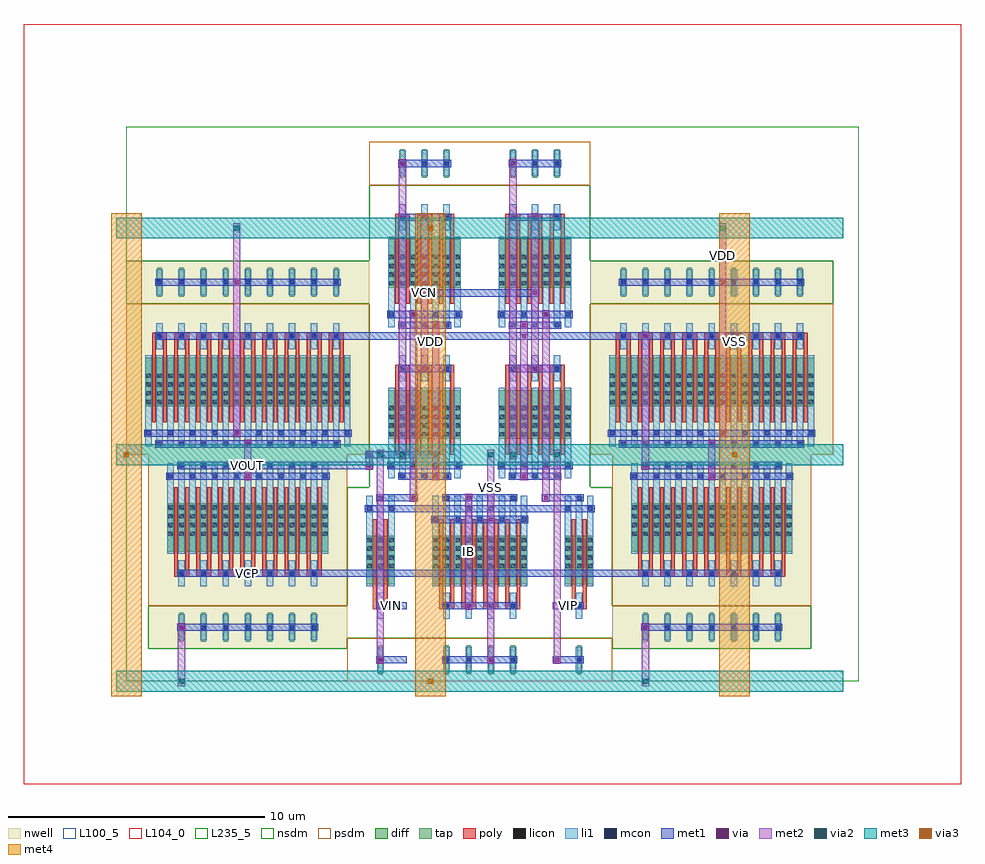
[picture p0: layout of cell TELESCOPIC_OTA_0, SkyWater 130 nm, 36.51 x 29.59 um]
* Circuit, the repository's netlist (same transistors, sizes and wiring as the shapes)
* NGSPICE file created from TELESCOPIC_OTA_0.ext - technology: sky130A

.subckt PMOS_S_43132956_X9_Y1_1774869329 a_200_252# a_230_378# w_0_0#
X0 a_230_378# a_200_252# w_0_0# w_0_0# sky130_fd_pr__pfet_01v8 ad=0.2646 pd=2.17 as=0.2646 ps=2.17 w=1.89 l=0.15 M=18
.ends

.subckt NMOS_4T_91638993_X3_Y2_1774869327 a_200_252# a_230_378# a_147_378# a_241_2408#
X0 a_230_378# a_200_252# a_147_378# a_241_2408# sky130_fd_pr__nfet_01v8 ad=0.2646 pd=2.17 as=0.2646 ps=2.17 w=1.89 l=0.15 M=12
.ends

.subckt PMOS_4T_19330511_X7_Y1_1774869328 a_200_252# a_230_378# w_0_0# a_147_378#
X0 a_230_378# a_200_252# a_147_378# w_0_0# sky130_fd_pr__pfet_01v8 ad=0.2646 pd=2.17 as=0.2646 ps=2.17 w=1.89 l=0.15 M=14
.ends

.subckt SCM_NMOS_27386274_X2_Y1_1774869330 a_200_252# a_402_378# a_147_378#
X0 a_402_378# a_200_252# a_147_378# a_147_378# sky130_fd_pr__nfet_01v8 ad=0.2646 pd=2.17 as=0.2646 ps=2.17 w=1.89 l=0.15 M=4
X1 a_200_252# a_200_252# a_147_378# a_147_378# sky130_fd_pr__nfet_01v8 ad=0.2646 pd=2.17 as=0.2646 ps=2.17 w=1.89 l=0.15 M=4
.ends

.subckt NMOS_4T_36089430_X1_Y1_1774869326 a_200_252# a_230_378# a_147_378# a_241_1232#
X0 a_230_378# a_200_252# a_147_378# a_241_1232# sky130_fd_pr__nfet_01v8 ad=0.2646 pd=2.17 as=0.50085 ps=4.31 w=1.89 l=0.15 M=2
.ends

.subckt TELESCOPIC_OTA_0 IB VCN VOUT VIP VIN VCP VSS VDD
XPMOS_S_43132956_X9_Y1_1774869329_0 m1_4010_1652# m1_914_1568# VDD PMOS_S_43132956_X9_Y1_1774869329
XNMOS_4T_91638993_X3_Y2_1774869327_0 VCN VOUT m1_2150_1400# VSS NMOS_4T_91638993_X3_Y2_1774869327
XPMOS_S_43132956_X9_Y1_1774869329_1 m1_4010_1652# m1_4526_1568# VDD PMOS_S_43132956_X9_Y1_1774869329
XNMOS_4T_91638993_X3_Y2_1774869327_1 VCN m1_4010_1652# m1_3236_1400# VSS NMOS_4T_91638993_X3_Y2_1774869327
XPMOS_4T_19330511_X7_Y1_1774869328_0 VCP VOUT VDD m1_914_1568# PMOS_4T_19330511_X7_Y1_1774869328
XPMOS_4T_19330511_X7_Y1_1774869328_1 VCP m1_4010_1652# VDD m1_4526_1568# PMOS_4T_19330511_X7_Y1_1774869328
XSCM_NMOS_27386274_X2_Y1_1774869330_0 IB m1_2838_1316# VSS SCM_NMOS_27386274_X2_Y1_1774869330
XNMOS_4T_36089430_X1_Y1_1774869326_0 VIN m1_2150_1400# m1_2838_1316# VSS NMOS_4T_36089430_X1_Y1_1774869326
XNMOS_4T_36089430_X1_Y1_1774869326_1 VIP m1_3236_1400# m1_2838_1316# VSS NMOS_4T_36089430_X1_Y1_1774869326
.ends

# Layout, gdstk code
from math import pi, radians
import gdstk
lib = gdstk.Library(unit=1e-6, precision=1e-09)
def R(c, l, rs):  # rectangles x0, y0, x1, y1
    for r in rs: c.add(gdstk.rectangle(r[:2], r[2:], *l))
def A(c, l, x, y, w, h, nx, ny, dx, dy):  # array of equal rectangles
    R(c, l, [(x+i*dx, y+j*dy, x+i*dx+w, y+j*dy+h) for i in range(nx) for j in range(ny)])
def P(c, l, *ps):  # polygons
    for p in ps: c.add(gdstk.Polygon(p, *l))
nwell = (64, 20)
diff = (65, 20)
tap = (65, 44)
poly = (66, 20)
licon = (66, 44)
li1 = (67, 20)
mcon = (67, 44)
met1 = (68, 20)
via = (68, 44)
met2 = (69, 20)
via2 = (69, 44)
met3 = (70, 20)
via3 = (70, 44)
met4 = (71, 20)
nsdm = (93, 44)
psdm = (94, 20)
L100_5 = (100, 5)
L104_0 = (104, 0)
L235_5 = (235, 5)

scm_nmos_27386274_x2_y1_ = lib.new_cell('SCM_NMOS_27386274_X2_Y1_1774869330')
R(scm_nmos_27386274_x2_y1_, diff, [(0.735,1.89,4.425,3.78)])
A(scm_nmos_27386274_x2_y1_, tap, 1.205, 6.16, 0.17, 1.12, 4, 1, 0.86, 0)
A(scm_nmos_27386274_x2_y1_, poly, 1, 1.26, 0.15, 3.36, 8, 1, 0.43, 0)
A(scm_nmos_27386274_x2_y1_, poly, 1, 4.485, 0.58, 0.27, 4, 1, 0.86, 0)
A(scm_nmos_27386274_x2_y1_, licon, 0.775, 1.97, 0.17, 0.17, 3, 4, 0.43, 0.34)
A(scm_nmos_27386274_x2_y1_, licon, 1.635, 1.97, 0.17, 0.17, 3, 4, 0.43, 0.34)
A(scm_nmos_27386274_x2_y1_, licon, 2.495, 1.97, 0.17, 0.17, 3, 4, 0.43, 0.34)
A(scm_nmos_27386274_x2_y1_, licon, 3.355, 1.97, 0.17, 0.17, 3, 4, 0.43, 0.34)
A(scm_nmos_27386274_x2_y1_, licon, 1.205, 4.535, 0.17, 0.17, 4, 2, 0.86, 2.1)
A(scm_nmos_27386274_x2_y1_, li1, 0.735, 0.335, 0.25, 3.53, 9, 1, 0.43, 0)
A(scm_nmos_27386274_x2_y1_, li1, 1.165, 4.115, 0.25, 1.01, 4, 2, 0.86, 2.1)
A(scm_nmos_27386274_x2_y1_, mcon, 0.775, 1.175, 0.17, 0.17, 5, 1, 0.86, 0)
A(scm_nmos_27386274_x2_y1_, mcon, 1.205, 4.535, 0.17, 0.17, 4, 2, 0.86, 2.1)
R(scm_nmos_27386274_x2_y1_, mcon, [(1.205,0.335,1.375,0.505), (3.785,0.335,3.955,0.505), (2.065,0.755,2.235,0.925), (2.925,0.755,3.095,0.925)])
R(scm_nmos_27386274_x2_y1_, met1, [(1.12,0.28,4.04,0.56), (1.98,0.7,3.18,0.98), (0.69,1.12,4.47,1.4), (1.12,4.48,4.04,4.76), (1.12,6.58,4.04,6.86)])
R(scm_nmos_27386274_x2_y1_, via, [(2.075,0.345,2.225,0.495), (2.935,1.185,3.085,1.335), (2.075,4.545,2.225,4.695), (2.935,6.645,3.085,6.795)])
R(scm_nmos_27386274_x2_y1_, met2, [(2.01,0.26,2.29,4.78), (2.87,1.1,3.15,6.88)])
R(scm_nmos_27386274_x2_y1_, nsdm, [(0,0,5.16,5.88)])
R(scm_nmos_27386274_x2_y1_, psdm, [(0,5.88,5.16,7.56)])
R(scm_nmos_27386274_x2_y1_, L100_5, [(0,0,5.16,7.56)])

pmos_s_43132956_x9_y1_17 = lib.new_cell('PMOS_S_43132956_X9_Y1_1774869329')
R(pmos_s_43132956_x9_y1_17, nwell, [(0,0,9.46,7.56)])
R(pmos_s_43132956_x9_y1_17, diff, [(0.735,1.89,8.725,3.78)])
A(pmos_s_43132956_x9_y1_17, tap, 1.205, 6.16, 0.17, 1.12, 9, 1, 0.86, 0)
A(pmos_s_43132956_x9_y1_17, poly, 1, 1.26, 0.15, 3.36, 18, 1, 0.43, 0)
A(pmos_s_43132956_x9_y1_17, poly, 1, 4.485, 0.58, 0.27, 9, 1, 0.86, 0)
A(pmos_s_43132956_x9_y1_17, licon, 0.775, 1.97, 0.17, 0.17, 3, 4, 0.43, 0.34)
A(pmos_s_43132956_x9_y1_17, licon, 1.635, 1.97, 0.17, 0.17, 3, 4, 0.43, 0.34)
A(pmos_s_43132956_x9_y1_17, licon, 2.495, 1.97, 0.17, 0.17, 3, 4, 0.43, 0.34)
A(pmos_s_43132956_x9_y1_17, licon, 3.355, 1.97, 0.17, 0.17, 3, 4, 0.43, 0.34)
A(pmos_s_43132956_x9_y1_17, licon, 4.215, 1.97, 0.17, 0.17, 3, 4, 0.43, 0.34)
A(pmos_s_43132956_x9_y1_17, licon, 5.075, 1.97, 0.17, 0.17, 3, 4, 0.43, 0.34)
A(pmos_s_43132956_x9_y1_17, licon, 5.935, 1.97, 0.17, 0.17, 3, 4, 0.43, 0.34)
A(pmos_s_43132956_x9_y1_17, licon, 6.795, 1.97, 0.17, 0.17, 3, 4, 0.43, 0.34)
A(pmos_s_43132956_x9_y1_17, licon, 7.655, 1.97, 0.17, 0.17, 3, 4, 0.43, 0.34)
A(pmos_s_43132956_x9_y1_17, licon, 1.205, 4.535, 0.17, 0.17, 9, 2, 0.86, 2.1)
A(pmos_s_43132956_x9_y1_17, li1, 0.735, 0.335, 0.25, 3.53, 19, 1, 0.43, 0)
A(pmos_s_43132956_x9_y1_17, li1, 1.165, 4.115, 0.25, 1.01, 9, 2, 0.86, 2.1)
A(pmos_s_43132956_x9_y1_17, mcon, 1.205, 0.335, 0.17, 0.17, 9, 2, 0.86, 4.2)
A(pmos_s_43132956_x9_y1_17, mcon, 0.775, 0.755, 0.17, 0.17, 10, 1, 0.86, 0)
A(pmos_s_43132956_x9_y1_17, mcon, 1.205, 6.635, 0.17, 0.17, 9, 1, 0.86, 0)
R(pmos_s_43132956_x9_y1_17, met1, [(1.12,0.28,8.34,0.56), (0.69,0.7,8.77,0.98), (1.12,4.48,8.34,4.76), (1.12,6.58,8.34,6.86)])
R(pmos_s_43132956_x9_y1_17, via, [(5.085,0.765,5.235,0.915), (5.085,6.645,5.235,6.795)])
R(pmos_s_43132956_x9_y1_17, met2, [(5.02,0.68,5.3,6.88)])
R(pmos_s_43132956_x9_y1_17, nsdm, [(0,5.88,9.46,7.56)])
R(pmos_s_43132956_x9_y1_17, psdm, [(0,0,9.46,5.88)])
R(pmos_s_43132956_x9_y1_17, L100_5, [(0,0,9.46,7.56)])

nmos_4t_91638993_x3_y2_1 = lib.new_cell('NMOS_4T_91638993_X3_Y2_1774869327')
R(nmos_4t_91638993_x3_y2_1, diff, [(0.735,1.89,3.565,3.78), (0.735,7.77,3.565,9.66)])
A(nmos_4t_91638993_x3_y2_1, tap, 1.205, 12.04, 0.17, 1.12, 3, 1, 0.86, 0)
A(nmos_4t_91638993_x3_y2_1, poly, 1, 1.26, 0.15, 3.36, 6, 2, 0.43, 5.88)
A(nmos_4t_91638993_x3_y2_1, poly, 1, 4.485, 0.58, 0.27, 3, 2, 0.86, 5.88)
A(nmos_4t_91638993_x3_y2_1, licon, 0.775, 1.97, 0.17, 0.17, 3, 4, 0.43, 0.34)
A(nmos_4t_91638993_x3_y2_1, licon, 1.635, 1.97, 0.17, 0.17, 3, 4, 0.43, 0.34)
A(nmos_4t_91638993_x3_y2_1, licon, 2.495, 1.97, 0.17, 0.17, 3, 4, 0.43, 0.34)
A(nmos_4t_91638993_x3_y2_1, licon, 1.205, 4.535, 0.17, 0.17, 3, 2, 0.86, 5.88)
A(nmos_4t_91638993_x3_y2_1, licon, 0.775, 7.85, 0.17, 0.17, 3, 4, 0.43, 0.34)
A(nmos_4t_91638993_x3_y2_1, licon, 1.635, 7.85, 0.17, 0.17, 3, 4, 0.43, 0.34)
A(nmos_4t_91638993_x3_y2_1, licon, 2.495, 7.85, 0.17, 0.17, 3, 4, 0.43, 0.34)
R(nmos_4t_91638993_x3_y2_1, licon, [(1.205,12.515,1.375,12.685), (1.205,12.515,1.375,12.685), (2.065,12.515,2.235,12.685), (2.065,12.515,2.235,12.685), (2.925,12.515,3.095,12.685), (2.925,12.515,3.095,12.685)])
A(nmos_4t_91638993_x3_y2_1, li1, 0.735, 0.335, 0.25, 3.53, 7, 2, 0.43, 5.88)
A(nmos_4t_91638993_x3_y2_1, li1, 1.165, 4.115, 0.25, 1.01, 3, 2, 0.86, 5.88)
A(nmos_4t_91638993_x3_y2_1, li1, 1.165, 12.095, 0.25, 1.01, 3, 1, 0.86, 0)
A(nmos_4t_91638993_x3_y2_1, mcon, 1.205, 0.335, 0.17, 0.17, 3, 2, 0.86, 4.2)
A(nmos_4t_91638993_x3_y2_1, mcon, 0.775, 0.755, 0.17, 0.17, 4, 2, 0.86, 5.88)
A(nmos_4t_91638993_x3_y2_1, mcon, 1.205, 6.215, 0.17, 0.17, 3, 2, 0.86, 4.2)
A(nmos_4t_91638993_x3_y2_1, mcon, 1.205, 12.515, 0.17, 0.17, 3, 1, 0.86, 0)
R(nmos_4t_91638993_x3_y2_1, met1, [(1.12,0.28,3.18,0.56), (0.69,0.7,3.61,0.98), (1.12,4.48,3.18,4.76), (1.12,6.16,3.18,6.44), (0.69,6.58,3.61,6.86), (1.12,10.36,3.18,10.64), (1.12,12.46,3.18,12.74)])
R(nmos_4t_91638993_x3_y2_1, via, [(1.645,0.345,1.795,0.495), (2.505,0.765,2.655,0.915), (2.075,4.545,2.225,4.695), (1.645,6.225,1.795,6.375), (2.505,6.645,2.655,6.795), (2.075,10.425,2.225,10.575)])
R(nmos_4t_91638993_x3_y2_1, met2, [(1.58,0.26,1.86,6.46), (2.44,0.68,2.72,6.88), (2.01,4.46,2.29,10.66)])
R(nmos_4t_91638993_x3_y2_1, nsdm, [(0,0,4.3,11.76)])
R(nmos_4t_91638993_x3_y2_1, psdm, [(0,11.76,4.3,13.44)])
R(nmos_4t_91638993_x3_y2_1, L100_5, [(0,0,4.3,13.44)])

nmos_4t_36089430_x1_y1_1 = lib.new_cell('NMOS_4T_36089430_X1_Y1_1774869326')
R(nmos_4t_36089430_x1_y1_1, diff, [(0.735,1.89,1.845,3.78)])
R(nmos_4t_36089430_x1_y1_1, tap, [(1.205,6.16,1.375,7.28)])
R(nmos_4t_36089430_x1_y1_1, poly, [(1,1.26,1.15,4.62), (1.43,1.26,1.58,4.62), (1,4.485,1.58,4.755)])
A(nmos_4t_36089430_x1_y1_1, licon, 0.775, 1.97, 0.17, 0.17, 3, 4, 0.43, 0.34)
R(nmos_4t_36089430_x1_y1_1, licon, [(1.205,4.535,1.375,4.705), (1.205,6.635,1.375,6.805)])
A(nmos_4t_36089430_x1_y1_1, li1, 0.735, 0.335, 0.25, 3.53, 3, 1, 0.43, 0)
R(nmos_4t_36089430_x1_y1_1, li1, [(1.165,4.115,1.415,5.125), (1.165,6.215,1.415,7.225)])
R(nmos_4t_36089430_x1_y1_1, mcon, [(1.205,0.335,1.375,0.505), (0.775,0.755,0.945,0.925), (1.635,0.755,1.805,0.925), (1.205,4.535,1.375,4.705), (1.205,6.635,1.375,6.805)])
R(nmos_4t_36089430_x1_y1_1, met1, [(0.26,0.28,1.46,0.56), (0.69,0.7,1.89,0.98), (0.26,4.48,1.46,4.76), (0.26,6.58,1.46,6.86)])
R(nmos_4t_36089430_x1_y1_1, nsdm, [(0,0,2.58,5.88)])
R(nmos_4t_36089430_x1_y1_1, psdm, [(0,5.88,2.58,7.56)])
R(nmos_4t_36089430_x1_y1_1, L100_5, [(0,0,2.58,7.56)])

pmos_4t_19330511_x7_y1_1 = lib.new_cell('PMOS_4T_19330511_X7_Y1_1774869328')
R(pmos_4t_19330511_x7_y1_1, nwell, [(0,0,7.74,7.56)])
R(pmos_4t_19330511_x7_y1_1, diff, [(0.735,1.89,7.005,3.78)])
A(pmos_4t_19330511_x7_y1_1, tap, 1.205, 6.16, 0.17, 1.12, 7, 1, 0.86, 0)
A(pmos_4t_19330511_x7_y1_1, poly, 1, 1.26, 0.15, 3.36, 14, 1, 0.43, 0)
A(pmos_4t_19330511_x7_y1_1, poly, 1, 4.485, 0.58, 0.27, 7, 1, 0.86, 0)
A(pmos_4t_19330511_x7_y1_1, licon, 0.775, 1.97, 0.17, 0.17, 3, 4, 0.43, 0.34)
A(pmos_4t_19330511_x7_y1_1, licon, 1.635, 1.97, 0.17, 0.17, 3, 4, 0.43, 0.34)
A(pmos_4t_19330511_x7_y1_1, licon, 2.495, 1.97, 0.17, 0.17, 3, 4, 0.43, 0.34)
A(pmos_4t_19330511_x7_y1_1, licon, 3.355, 1.97, 0.17, 0.17, 3, 4, 0.43, 0.34)
A(pmos_4t_19330511_x7_y1_1, licon, 4.215, 1.97, 0.17, 0.17, 3, 4, 0.43, 0.34)
A(pmos_4t_19330511_x7_y1_1, licon, 5.075, 1.97, 0.17, 0.17, 3, 4, 0.43, 0.34)
A(pmos_4t_19330511_x7_y1_1, licon, 5.935, 1.97, 0.17, 0.17, 3, 4, 0.43, 0.34)
A(pmos_4t_19330511_x7_y1_1, licon, 1.205, 4.535, 0.17, 0.17, 7, 2, 0.86, 2.1)
A(pmos_4t_19330511_x7_y1_1, li1, 0.735, 0.335, 0.25, 3.53, 15, 1, 0.43, 0)
A(pmos_4t_19330511_x7_y1_1, li1, 1.165, 4.115, 0.25, 1.01, 7, 2, 0.86, 2.1)
A(pmos_4t_19330511_x7_y1_1, mcon, 1.205, 0.335, 0.17, 0.17, 7, 2, 0.86, 4.2)
A(pmos_4t_19330511_x7_y1_1, mcon, 0.775, 0.755, 0.17, 0.17, 8, 1, 0.86, 0)
A(pmos_4t_19330511_x7_y1_1, mcon, 1.205, 6.635, 0.17, 0.17, 7, 1, 0.86, 0)
R(pmos_4t_19330511_x7_y1_1, met1, [(1.12,0.28,6.62,0.56), (0.69,0.7,7.05,0.98), (1.12,4.48,6.62,4.76), (1.12,6.58,6.62,6.86)])
R(pmos_4t_19330511_x7_y1_1, nsdm, [(0,5.88,7.74,7.56)])
R(pmos_4t_19330511_x7_y1_1, psdm, [(0,0,7.74,5.88)])
R(pmos_4t_19330511_x7_y1_1, L100_5, [(0,0,7.74,7.56)])

telescopic_ota_0 = lib.new_cell('TELESCOPIC_OTA_0')
R(telescopic_ota_0, met1, [(9.73,0.7,10.05,0.98), (9.73,0.7,10.05,0.98), (16.61,0.7,16.93,0.98), (16.61,0.7,16.93,0.98), (16.61,0.7,16.93,0.98), (1.99,1.96,2.31,2.24), (1.99,1.96,2.31,2.24), (20.05,1.96,20.37,2.24), (20.05,1.96,20.37,2.24), (20.05,1.96,20.37,2.24), (7.31,4.06,20.21,4.34), (10.32,6.58,13.33,6.86), (14.19,6.58,17.2,6.86), (10.75,7,11.18,7.28), (11.02,7,11.34,7.28), (11.02,7,11.34,7.28), (16.18,7,16.5,7.28), (16.18,7,16.5,7.28), (16.34,7,16.77,7.28), (4.57,7.84,4.89,8.12), (4.57,7.84,4.89,8.12), (22.63,7.84,22.95,8.12), (22.63,7.84,22.95,8.12), (7.31,8.26,9.46,8.54), (9.3,8.26,9.62,8.54), (9.3,8.26,9.62,8.54), (20.05,8.26,20.37,8.54), (20.05,8.26,20.37,8.54), (9.3,8.68,9.62,8.96), (9.3,8.68,9.62,8.96), (9.46,8.68,12.04,8.96), (11.88,8.68,12.2,8.96), (11.88,8.68,12.2,8.96), (4.57,9.1,4.89,9.38), (4.57,9.1,4.89,9.38), (22.63,9.1,22.95,9.38), (22.63,9.1,22.95,9.38), (8.17,13.3,15.48,13.58), (15.32,13.3,15.64,13.58), (15.32,13.3,15.64,13.58), (15.32,13.3,15.64,13.58), (15.32,13.3,15.64,13.58), (15.32,13.3,15.64,13.58), (15.32,13.3,15.64,13.58), (15.48,13.3,19.35,13.58), (20.05,13.3,20.37,13.58), (20.05,13.3,20.37,13.58), (11.45,14.98,11.77,15.26), (11.45,14.98,11.77,15.26), (11.61,14.98,15.91,15.26), (15.75,14.98,16.07,15.26), (15.75,14.98,16.07,15.26), (10.59,20.02,10.91,20.3), (10.59,20.02,10.91,20.3), (10.59,20.02,10.91,20.3), (10.59,20.02,10.91,20.3), (14.89,20.02,15.21,20.3), (14.89,20.02,15.21,20.3), (14.89,20.02,15.21,20.3), (14.89,20.02,15.21,20.3), (14.89,20.02,15.21,20.3)])
P(telescopic_ota_0, met1, [(0,0),(0,0),(0,0),(0,0)],
  [(0,0),(0,0),(0,0),(0,0)],
  [(0,0),(0,0),(0,0),(0,0)],
  [(0,0),(0,0),(0,0),(0,0)],
  [(0,0),(0,0),(0,0),(0,0)],
  [(0,0),(0,0),(0,0),(0,0)],
  [(0,0),(0,0),(0,0),(0,0)],
  [(0,0),(0,0),(0,0),(0,0)],
  [(0,0),(0,0),(0,0),(0,0)],
  [(0,0),(0,0),(0,0),(0,0)],
  [(0,0),(0,0),(0,0),(0,0)],
  [(0,0),(0,0),(0,0),(0,0)],
  [(0,0),(0,0),(0,0),(0,0)],
  [(0,0),(0,0),(0,0),(0,0)],
  [(0,0),(0,0),(0,0),(0,0)],
  [(0,0),(0,0),(0,0),(0,0)],
  [(0,0),(0,0),(0,0),(0,0)],
  [(0,0),(0,0),(0,0),(0,0)],
  [(0,0),(0,0),(0,0),(0,0)],
  [(0,0),(0,0),(0,0),(0,0)],
  [(0,0),(0,0),(0,0),(0,0)],
  [(0,0),(0,0),(0,0),(0,0)],
  [(0,0),(0,0),(0,0),(0,0)],
  [(0,0),(0,0),(0,0),(0,0)],
  [(0,0),(0,0),(0,0),(0,0)],
  [(0,0),(0,0),(0,0),(0,0)],
  [(0,0),(0,0),(0,0),(0,0)])
R(telescopic_ota_0, via, [(9.815,0.765,9.965,0.915), (9.815,0.765,9.965,0.915), (16.695,0.765,16.845,0.915), (16.695,0.765,16.845,0.915), (16.695,0.765,16.845,0.915), (2.075,2.025,2.225,2.175), (2.075,2.025,2.225,2.175), (20.135,2.025,20.285,2.175), (20.135,2.025,20.285,2.175), (20.135,2.025,20.285,2.175), (11.105,7.065,11.255,7.215), (11.105,7.065,11.255,7.215), (16.265,7.065,16.415,7.215), (16.265,7.065,16.415,7.215), (4.655,7.905,4.805,8.055), (4.655,7.905,4.805,8.055), (22.715,7.905,22.865,8.055), (22.715,7.905,22.865,8.055), (9.385,8.325,9.535,8.475), (9.385,8.325,9.535,8.475), (20.135,8.325,20.285,8.475), (20.135,8.325,20.285,8.475), (9.385,8.745,9.535,8.895), (9.385,8.745,9.535,8.895), (11.965,8.745,12.115,8.895), (11.965,8.745,12.115,8.895), (4.655,9.165,4.805,9.315), (4.655,9.165,4.805,9.315), (22.715,9.165,22.865,9.315), (22.715,9.165,22.865,9.315), (15.405,13.365,15.555,13.515), (15.405,13.365,15.555,13.515), (15.405,13.365,15.555,13.515), (15.405,13.365,15.555,13.515), (15.405,13.365,15.555,13.515), (15.405,13.365,15.555,13.515), (20.135,13.365,20.285,13.515), (20.135,13.365,20.285,13.515), (11.535,15.045,11.685,15.195), (11.535,15.045,11.685,15.195), (15.835,15.045,15.985,15.195), (15.835,15.045,15.985,15.195), (10.675,20.085,10.825,20.235), (10.675,20.085,10.825,20.235), (10.675,20.085,10.825,20.235), (10.675,20.085,10.825,20.235), (14.975,20.085,15.125,20.235), (14.975,20.085,15.125,20.235), (14.975,20.085,15.125,20.235), (14.975,20.085,15.125,20.235), (14.975,20.085,15.125,20.235)])
R(telescopic_ota_0, met2, [(2.01,-0.185,2.29,0.185), (2.01,-0.185,2.29,0.185), (20.07,-0.185,20.35,0.185), (20.07,-0.185,20.35,0.185), (20.07,-0.185,20.35,0.185), (2.01,0,2.29,2.1), (20.07,0,20.35,2.1), (9.75,0.68,10.03,1), (9.75,0.68,10.03,1), (16.63,0.68,16.91,1), (16.63,0.68,16.91,1), (16.63,0.68,16.91,1), (9.75,0.84,10.03,8.82), (16.63,0.84,16.91,8.82), (2.01,1.94,2.29,2.26), (2.01,1.94,2.29,2.26), (20.07,1.94,20.35,2.26), (20.07,1.94,20.35,2.26), (20.07,1.94,20.35,2.26), (14.05,6.3,14.33,8.82), (11.04,6.98,11.32,7.3), (11.04,6.98,11.32,7.3), (16.2,6.98,16.48,7.3), (16.2,6.98,16.48,7.3), (11.04,7.14,11.32,8.4), (16.2,7.14,16.48,8.4), (4.59,7.82,4.87,8.14), (4.59,7.82,4.87,8.14), (22.65,7.82,22.93,8.14), (22.65,7.82,22.93,8.14), (4.59,7.98,4.87,9.24), (22.65,7.98,22.93,9.24), (9.32,8.24,9.6,8.56), (9.32,8.24,9.6,8.56), (20.07,8.24,20.35,8.56), (20.07,8.24,20.35,8.56), (9.32,8.4,9.6,8.82), (20.07,8.4,20.35,13.44), (9.75,8.635,10.03,9.005), (9.75,8.635,10.03,9.005), (10.61,8.635,10.89,9.005), (10.61,8.635,10.89,9.005), (10.61,8.635,10.89,9.005), (10.61,8.635,10.89,9.005), (14.05,8.635,14.33,9.005), (14.05,8.635,14.33,9.005), (14.05,8.635,14.33,9.005), (14.05,8.635,14.33,9.005), (14.05,8.635,14.33,9.005), (14.05,8.635,14.33,9.005), (14.91,8.635,15.19,9.005), (14.91,8.635,15.19,9.005), (14.91,8.635,15.19,9.005), (14.91,8.635,15.19,9.005), (14.91,8.635,15.19,9.005), (16.63,8.635,16.91,9.005), (16.63,8.635,16.91,9.005), (16.63,8.635,16.91,9.005), (9.32,8.66,9.6,8.98), (9.32,8.66,9.6,8.98), (11.9,8.66,12.18,8.98), (11.9,8.66,12.18,8.98), (10.61,8.82,10.89,20.16), (14.91,8.82,15.19,20.16), (4.59,9.08,4.87,9.4), (4.59,9.08,4.87,9.4), (22.65,9.08,22.93,9.4), (22.65,9.08,22.93,9.4), (15.34,13.28,15.62,13.6), (15.34,13.28,15.62,13.6), (15.34,13.28,15.62,13.6), (15.34,13.28,15.62,13.6), (15.34,13.28,15.62,13.6), (15.34,13.28,15.62,13.6), (20.07,13.28,20.35,13.6), (20.07,13.28,20.35,13.6), (11.47,14.96,11.75,15.28), (11.47,14.96,11.75,15.28), (15.77,14.96,16.05,15.28), (15.77,14.96,16.05,15.28), (4.16,15.54,4.44,17.64), (23.08,15.54,23.36,17.64), (4.16,17.455,4.44,17.825), (4.16,17.455,4.44,17.825), (4.16,17.455,4.44,17.825), (4.16,17.455,4.44,17.825), (23.08,17.455,23.36,17.825), (23.08,17.455,23.36,17.825), (23.08,17.455,23.36,17.825), (23.08,17.455,23.36,17.825), (23.08,17.455,23.36,17.825), (10.61,20,10.89,20.32), (10.61,20,10.89,20.32), (10.61,20,10.89,20.32), (10.61,20,10.89,20.32), (14.91,20,15.19,20.32), (14.91,20,15.19,20.32), (14.91,20,15.19,20.32), (14.91,20,15.19,20.32), (14.91,20,15.19,20.32)])
P(telescopic_ota_0, met2, [(0,0),(0,0),(0,0),(0,0)],
  [(0,0),(0,0),(0,0),(0,0)],
  [(0,0),(0,0),(0,0),(0,0)],
  [(0,0),(0,0),(0,0),(0,0)],
  [(0,0),(0,0),(0,0),(0,0)],
  [(0,0),(0,0),(0,0),(0,0)],
  [(0,0),(0,0),(0,0),(0,0)],
  [(0,0),(0,0),(0,0),(0,0)],
  [(0,0),(0,0),(0,0),(0,0)],
  [(0,0),(0,0),(0,0),(0,0)],
  [(0,0),(0,0),(0,0),(0,0)],
  [(0,0),(0,0),(0,0),(0,0)])
R(telescopic_ota_0, via2, [(2.05,-0.1,2.25,0.1), (2.05,-0.1,2.25,0.1), (20.11,-0.1,20.31,0.1), (20.11,-0.1,20.31,0.1), (20.11,-0.1,20.31,0.1), (9.79,8.72,9.99,8.92), (9.79,8.72,9.99,8.92), (10.65,8.72,10.85,8.92), (10.65,8.72,10.85,8.92), (10.65,8.72,10.85,8.92), (10.65,8.72,10.85,8.92), (14.09,8.72,14.29,8.92), (14.09,8.72,14.29,8.92), (14.09,8.72,14.29,8.92), (14.09,8.72,14.29,8.92), (14.09,8.72,14.29,8.92), (14.09,8.72,14.29,8.92), (14.95,8.72,15.15,8.92), (14.95,8.72,15.15,8.92), (14.95,8.72,15.15,8.92), (14.95,8.72,15.15,8.92), (14.95,8.72,15.15,8.92), (16.67,8.72,16.87,8.92), (16.67,8.72,16.87,8.92), (16.67,8.72,16.87,8.92), (4.2,17.54,4.4,17.74), (4.2,17.54,4.4,17.74), (4.2,17.54,4.4,17.74), (4.2,17.54,4.4,17.74), (23.12,17.54,23.32,17.74), (23.12,17.54,23.32,17.74), (23.12,17.54,23.32,17.74), (23.12,17.54,23.32,17.74), (23.12,17.54,23.32,17.74)])
A(telescopic_ota_0, met3, -0.4, -0.4, 4.24, 0.8, 3, 3, 3.44, 8.82)
A(telescopic_ota_0, met3, 9.92, -0.4, 2.32, 0.8, 1, 3, 0, 8.82)
A(telescopic_ota_0, met3, 11.44, -0.4, 2.72, 0.8, 1, 3, 0, 8.82)
A(telescopic_ota_0, met3, 13.36, -0.4, 4.24, 0.8, 1, 3, 0, 8.82)
A(telescopic_ota_0, met3, 16.8, -0.4, 4.24, 0.8, 1, 3, 0, 8.82)
A(telescopic_ota_0, met3, 20.24, -0.4, 3.84, 0.8, 1, 3, 0, 8.82)
A(telescopic_ota_0, met3, 23.28, -0.4, 1.2, 0.8, 1, 3, 0, 8.82)
A(telescopic_ota_0, met3, 23.68, -0.4, 4.24, 0.8, 1, 3, 0, 8.82)
R(telescopic_ota_0, met3, [(1.985,-0.4,2.315,0.4), (1.985,-0.4,2.315,0.4), (11.675,-0.4,12.005,0.4), (20.045,-0.4,20.375,0.4), (20.045,-0.4,20.375,0.4), (20.045,-0.4,20.375,0.4), (-0.165,8.42,0.165,9.22), (9.725,8.42,10.055,9.22), (9.725,8.42,10.055,9.22), (10.585,8.42,10.915,9.22), (10.585,8.42,10.915,9.22), (10.585,8.42,10.915,9.22), (10.585,8.42,10.915,9.22), (14.025,8.42,14.355,9.22), (14.025,8.42,14.355,9.22), (14.025,8.42,14.355,9.22), (14.025,8.42,14.355,9.22), (14.025,8.42,14.355,9.22), (14.025,8.42,14.355,9.22), (14.885,8.42,15.215,9.22), (14.885,8.42,15.215,9.22), (14.885,8.42,15.215,9.22), (14.885,8.42,15.215,9.22), (14.885,8.42,15.215,9.22), (16.605,8.42,16.935,9.22), (16.605,8.42,16.935,9.22), (16.605,8.42,16.935,9.22), (23.515,8.42,23.845,9.22), (4.135,17.24,4.465,18.04), (4.135,17.24,4.465,18.04), (4.135,17.24,4.465,18.04), (4.135,17.24,4.465,18.04), (11.675,17.24,12.005,18.04), (23.055,17.24,23.385,18.04), (23.055,17.24,23.385,18.04), (23.055,17.24,23.385,18.04), (23.055,17.24,23.385,18.04), (23.055,17.24,23.385,18.04)])
R(telescopic_ota_0, via3, [(11.74,-0.1,11.94,0.1), (-0.1,8.72,0.1,8.92), (23.58,8.72,23.78,8.92), (11.74,17.54,11.94,17.74)])
A(telescopic_ota_0, met4, -0.59, -0.59, 1.18, 10, 3, 2, 11.84, 8.82)
R(telescopic_ota_0, met4, [(11.25,-0.165,12.43,0.165), (-0.59,8.655,0.59,8.985), (23.09,8.655,24.27,8.985), (11.25,17.475,12.43,17.805)])
R(telescopic_ota_0, L104_0, [(-4,-4,32.51,25.59)])
R(telescopic_ota_0, L235_5, [(0,0,28.51,21.59)])
telescopic_ota_0.add(gdstk.Reference(scm_nmos_27386274_x2_y1_, (11.18,7.56), x_reflection=True))
telescopic_ota_0.add(gdstk.Reference(pmos_s_43132956_x9_y1_17, (18.06,8.82)))
telescopic_ota_0.add(gdstk.Reference(pmos_s_43132956_x9_y1_17, (9.46,8.82), rotation=pi, x_reflection=True))
telescopic_ota_0.add(gdstk.Reference(nmos_4t_91638993_x3_y2_1, (13.76,7.56)))
telescopic_ota_0.add(gdstk.Reference(nmos_4t_91638993_x3_y2_1, (13.76,7.56), rotation=pi, x_reflection=True))
telescopic_ota_0.add(gdstk.Reference(nmos_4t_36089430_x1_y1_1, (16.34,7.56), x_reflection=True))
telescopic_ota_0.add(gdstk.Reference(nmos_4t_36089430_x1_y1_1, (11.18,7.56), rotation=pi))
telescopic_ota_0.add(gdstk.Reference(pmos_4t_19330511_x7_y1_1, (26.66,8.82), rotation=pi))
telescopic_ota_0.add(gdstk.Reference(pmos_4t_19330511_x7_y1_1, (0.86,8.82), x_reflection=True))
telescopic_ota_0.add(gdstk.Label('IB', (13.33,5.04), layer=69, texttype=5))
telescopic_ota_0.add(gdstk.Label('VCN', (11.61,15.12), layer=69, texttype=5))
telescopic_ota_0.add(gdstk.Label('VOUT', (4.73,8.4), layer=68, texttype=5))
telescopic_ota_0.add(gdstk.Label('VIP', (17.2,2.94), layer=68, texttype=5))
telescopic_ota_0.add(gdstk.Label('VIN', (10.32,2.94), layer=68, texttype=5))
telescopic_ota_0.add(gdstk.Label('VCP', (4.73,4.2), layer=68, texttype=5))
telescopic_ota_0.add(gdstk.Label('VSS', (14.19,7.56), layer=69, texttype=5))
telescopic_ota_0.add(gdstk.Label('VSS', (23.68,13.23), layer=71, texttype=5))
telescopic_ota_0.add(gdstk.Label('VSS', (23.68,13.23), layer=71, texttype=5))
telescopic_ota_0.add(gdstk.Label('VSS', (23.68,13.23), layer=71, texttype=5))
telescopic_ota_0.add(gdstk.Label('VSS', (23.68,13.23), layer=71, texttype=5))
telescopic_ota_0.add(gdstk.Label('VSS', (23.68,13.23), layer=71, texttype=5))
telescopic_ota_0.add(gdstk.Label('VSS', (23.68,13.23), layer=71, texttype=5))
telescopic_ota_0.add(gdstk.Label('VSS', (23.68,13.23), layer=71, texttype=5))
telescopic_ota_0.add(gdstk.Label('VSS', (23.68,13.23), layer=71, texttype=5))
telescopic_ota_0.add(gdstk.Label('VSS', (23.68,13.23), layer=71, texttype=5))
telescopic_ota_0.add(gdstk.Label('VSS', (23.68,13.23), layer=71, texttype=5))
telescopic_ota_0.add(gdstk.Label('VSS', (23.68,13.23), layer=71, texttype=5))
telescopic_ota_0.add(gdstk.Label('VSS', (23.68,13.23), layer=71, texttype=5))
telescopic_ota_0.add(gdstk.Label('VSS', (23.68,13.23), layer=71, texttype=5))
telescopic_ota_0.add(gdstk.Label('VSS', (23.68,13.23), layer=71, texttype=5))
telescopic_ota_0.add(gdstk.Label('VDD', (23.22,16.59), layer=69, texttype=5))
telescopic_ota_0.add(gdstk.Label('VDD', (11.84,13.23), layer=71, texttype=5))
telescopic_ota_0.add(gdstk.Label('VDD', (11.84,13.23), layer=71, texttype=5))
telescopic_ota_0.add(gdstk.Label('VDD', (11.84,13.23), layer=71, texttype=5))
telescopic_ota_0.add(gdstk.Label('VDD', (11.84,13.23), layer=71, texttype=5))
telescopic_ota_0.add(gdstk.Label('VDD', (11.84,13.23), layer=71, texttype=5))
telescopic_ota_0.add(gdstk.Label('VDD', (11.84,13.23), layer=71, texttype=5))
telescopic_ota_0.add(gdstk.Label('VDD', (11.84,13.23), layer=71, texttype=5))
telescopic_ota_0.add(gdstk.Label('VDD', (11.84,13.23), layer=71, texttype=5))
telescopic_ota_0.add(gdstk.Label('VDD', (11.84,13.23), layer=71, texttype=5))
telescopic_ota_0.add(gdstk.Label('VDD', (11.84,13.23), layer=71, texttype=5))

lib.write_gds('TELESCOPIC_OTA_0.gds')
